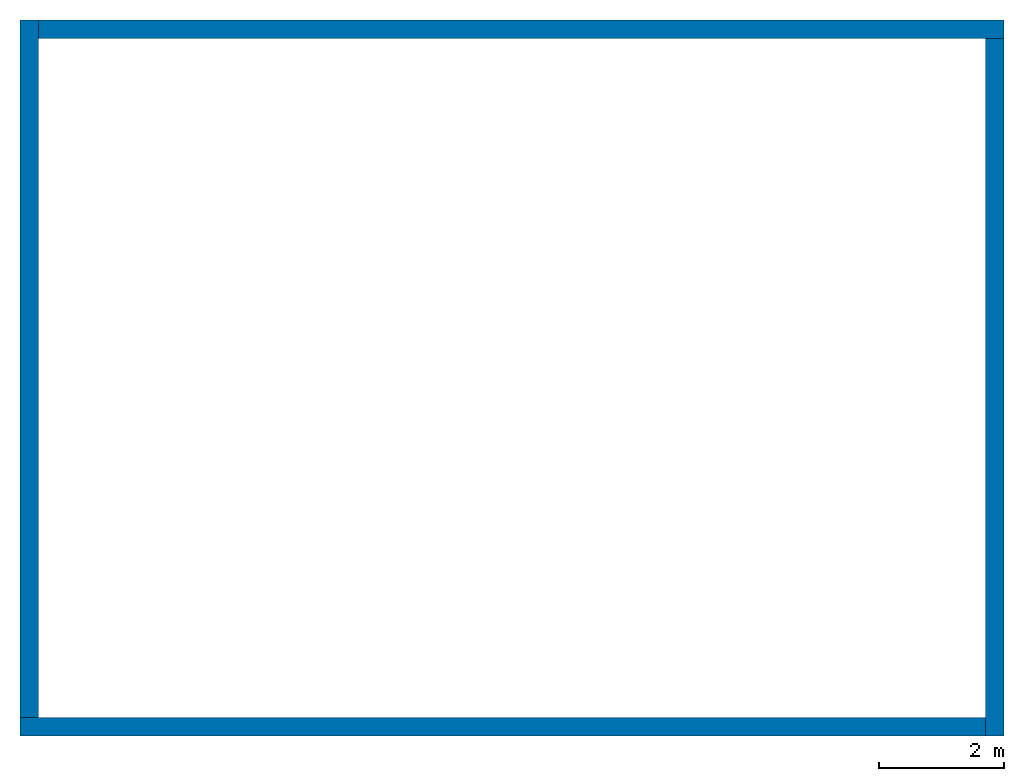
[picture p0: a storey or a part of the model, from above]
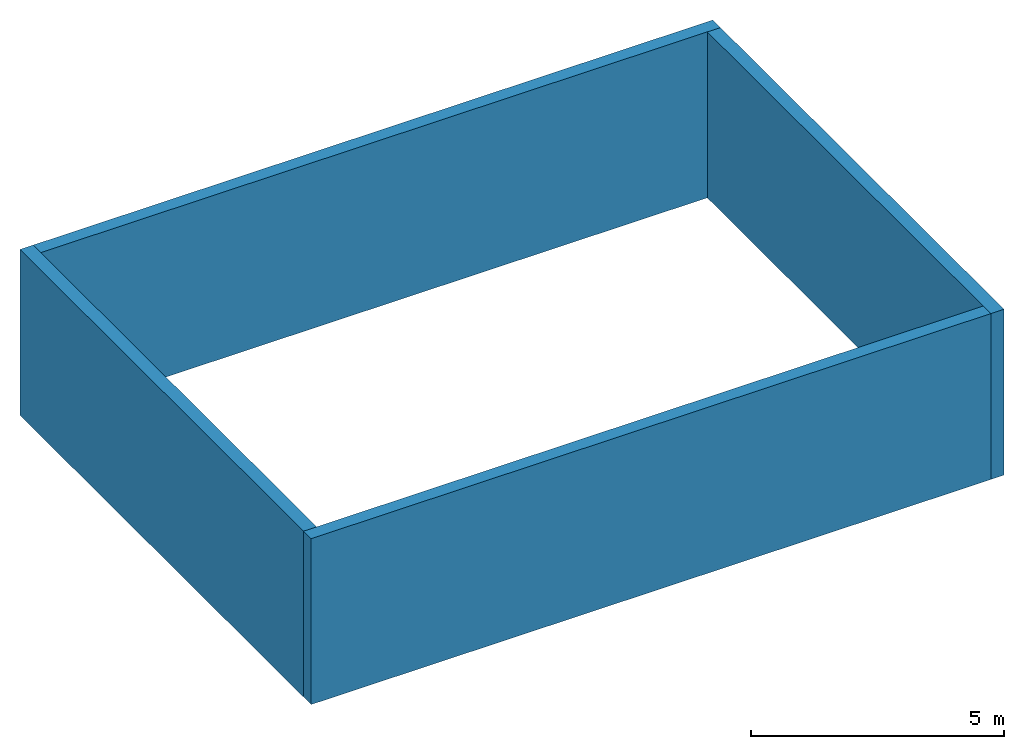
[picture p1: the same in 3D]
Properties of the parts of a building model (IFC2X3)

# File
Description: ViewDefinition [CoordinationView_V2.0]
File name: 2012C-006
Time: 2013-12-05T17:56:39
Written by: The EXPRESS Data Manager Version 5.01.0100.02.64mod : 6 Jun 2012
Made in: 20130308_1515(x64) - Exporter 3.5.0.0 - Alternate UI 2.5.0.0
Comment: STEP Physical File produced by: The EXPRESS Data Manager Version 5.01.0100.02.64mod : 6 Jun 2012 * Module: EDMstepFileFactory/EDMstandAlone * Creation date: Thu Dec 05 17:56:39 2013 * Host: MDR_LPTP_BTO * Database: C:\Users\Martijn\AppData\Local\Temp\{A570B49A-0B47-45CF-954C-E44DFDC6816B}\ifc * Database version: 5507 * Database creation date: Thu Dec 05 17:56:38 2013 * Schema: IFC2X3 * Model: DataRepository.ifc * Model creation date: Thu Dec 05 17:56:39 2013 * Header model: DataRepository.ifc_HeaderModel * Header model creation date: Thu Dec 05 17:56:39 2013 * EDMuser: sdai-user * EDMgroup: sdai-group * License ID and type: 5605 : Permanent license. Expiry date: * EDMstepFileFactory options: 020000

# IfcProject, 2012C-006
LongName: Dutch Revit Standards; Phase: VOORLOPIG

# IfcSite, Default
RefLatitude: 42, 24, 53, 508911; RefLongitude: -71, -15, -29, -58837; RefElevation: 0 mm

# IfcBuilding
Pset_BuildingCommon - NumberOfStoreys: 1

# IfcBuildingStorey, 00_begane grond
LongName: 00_begane grond; Elevation: 0 mm

# IfcWallStandardCase: Basic Wall:20_WA_wand_generiek_300 (4)
In: 00_begane grond
Type - PredefinedType: STANDARD; Material: Default 300 mm
Pset_WallCommon - Reference: 20_WA_wand_generiek_300; LoadBearing: no; ExtendToStructure: no; IsExternal: yes; SurfaceSpreadOfFlame: A1; Combustible: yes
PSet_COBIE - NominalWidth: 300
Name (Basic Wall:20_WA_wand_generiek_300:...) | NominalLength
431948 | 15500
431949 | 11200
431950 | 15500 | Pset_WallCommon - FireRating: 75; AcousticRating: Acousting Rate; Compartmentation: yes
431951 | 11200
